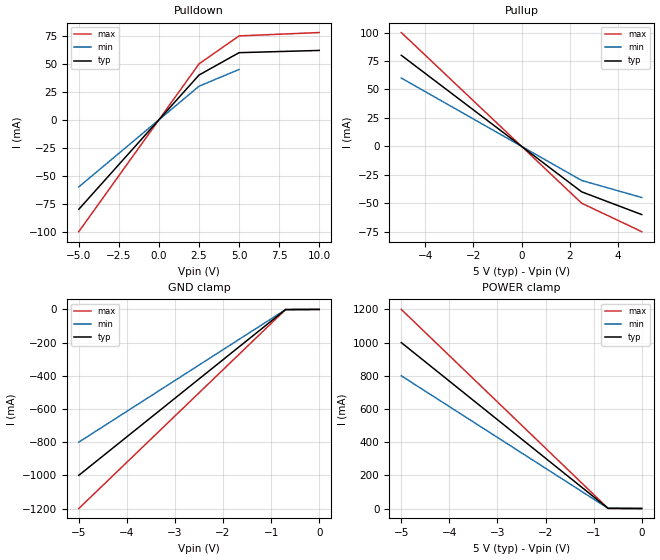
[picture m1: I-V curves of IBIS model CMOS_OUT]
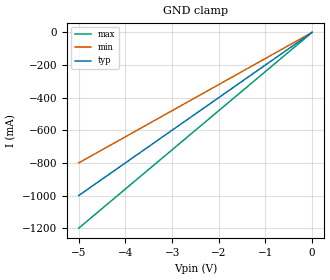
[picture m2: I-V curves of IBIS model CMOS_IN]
[IBIS Ver]   4.2
[File Name]  test_buffer.ibs
[Component]  TESTCHIP
[Manufacturer] BHDL Test Suite
[Package]
| variable   typ   min   max
R_pkg   50.00m  30.00m  70.00m
L_pkg   5.00nH  3.00nH  8.00nH
C_pkg   0.50pF  0.30pF  0.80pF
[Pin]  signal_name  model_name
1   OUT1   CMOS_OUT
2   IN1   CMOS_IN
3   GND   GND
4   VCC   POWER
5   SEL   SELPIN
[Model Selector] SELPIN
CMOS_OUT   default output
CMOS_IN   alternate input
| Models and submodels in the file (2): CMOS_OUT (Output), CMOS_IN (Input)
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[Model]  CMOS_OUT
Model_type   Output
C_comp   3.5pF  3.0pF  4.0pF
[Voltage Range]  5.0V  4.5V  5.5V
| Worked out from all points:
|   slope of the pulldown table from 0 to 0.75 V, typ, clamps not added: 62.5 ohm
|   slope of the pullup table from 0 to 0.75 V, typ, clamps not added: 62.5 ohm
[Pulldown]
| V   I(typ)   I(min)   I(max)
-5V       -80mA      -60mA      -100mA
0V        0A         0A         0A
2.5V      40mA       30mA       50mA
5V        60mA       45mA       75mA
10V       62mA       NA         78mA
[Pullup]
| V(=Vcc-Vpin)  I(typ)   I(min)   I(max)
-5V       80mA       60mA       100mA
0V        0A         0A         0A
2.5V      -40mA      -30mA      -50mA
5V        -60mA      -45mA      -75mA
[GND Clamp]
-5V       -1A        -800mA     -1.2A
-700mV    -1mA       -1mA       -1mA
0V        0A         0A         0A
[POWER Clamp]
-5V       1A         800mA      1.2A
-700mV    1mA        1mA        1mA
0V        0A         0A         0A
[Ramp]
dV/dt_r   2.0/1.0n   1.5/1.2n  2.5/0.8n
dV/dt_f   2.0/1.1n   1.5/1.3n  2.5/0.9n
[Model]  CMOS_IN
Model_type   Input
[Voltage Range]  5.0V  4.5V  5.5V
[GND Clamp]
-5V       -1A        -800mA     -1.2A
0V        0A         0A         0A
